VERSION 5.7 ;
  NOWIREEXTENSIONATPIN ON ;
  DIVIDERCHAR "/" ;
  BUSBITCHARS "[]" ;
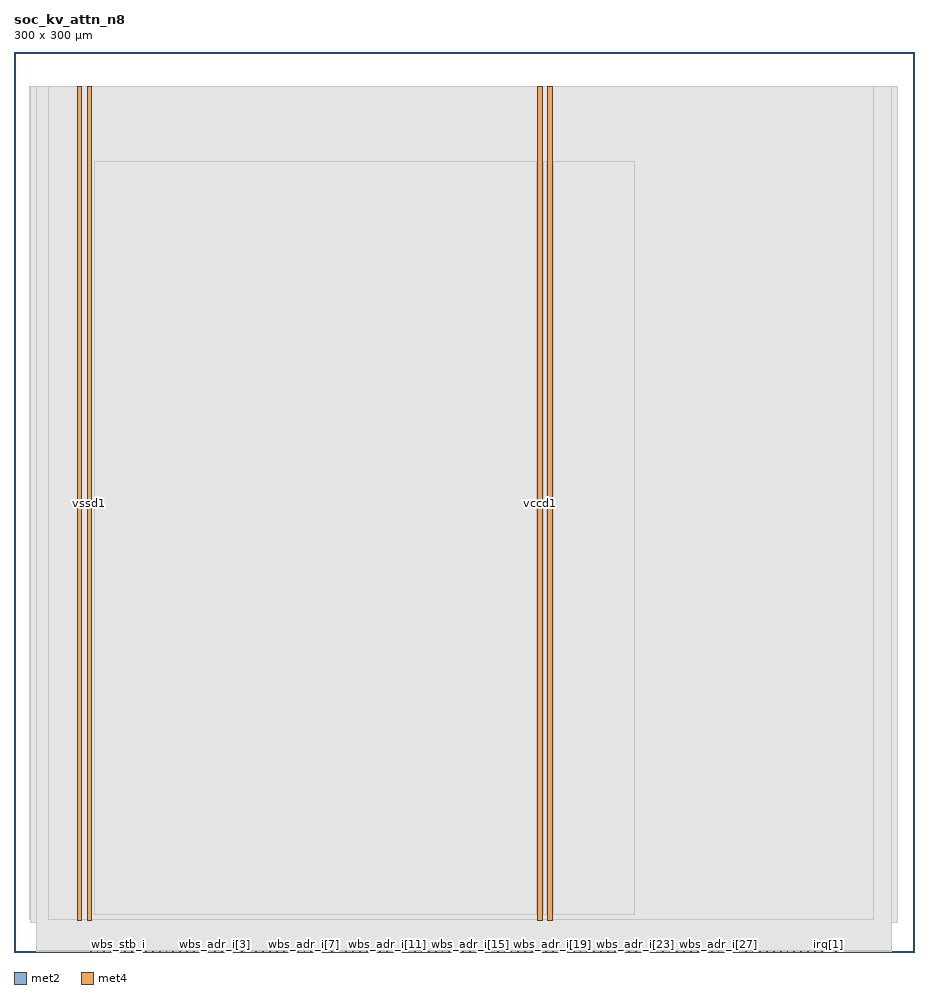
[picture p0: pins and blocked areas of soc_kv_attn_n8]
MACRO soc_kv_attn_n8
  CLASS BLOCK ;
  FOREIGN soc_kv_attn_n8 ;
  ORIGIN 0.000 0.000 ;
  SIZE 300.000 BY 300.000 ;
  PIN irq[0]
    DIRECTION OUTPUT ;
    USE SIGNAL ;
    ANTENNADIFFAREA 2.673000 ;
    PORT
      LAYER met2 ;
        RECT 269.190 0.000 269.470 0.280 ;
    END
  END irq[0]
  PIN irq[1]
    DIRECTION OUTPUT ;
    USE SIGNAL ;
    PORT
      LAYER met2 ;
        RECT 271.490 0.000 271.770 0.280 ;
    END
  END irq[1]
  PIN irq[2]
    DIRECTION OUTPUT ;
    USE SIGNAL ;
    PORT
      LAYER met2 ;
        RECT 273.790 0.000 274.070 0.280 ;
    END
  END irq[2]
  PIN vccd1
    DIRECTION INOUT ;
    USE POWER ;
    PORT
      LAYER met4 ;
        RECT 21.040 10.640 22.640 288.560 ;
    END
    PORT
      LAYER met4 ;
        RECT 174.640 10.640 176.240 288.560 ;
    END
  END vccd1
  PIN vssd1
    DIRECTION INOUT ;
    USE GROUND ;
    PORT
      LAYER met4 ;
        RECT 24.340 10.640 25.940 288.560 ;
    END
    PORT
      LAYER met4 ;
        RECT 177.940 10.640 179.540 288.560 ;
    END
  END vssd1
  PIN wb_clk_i
    DIRECTION INPUT ;
    USE SIGNAL ;
    ANTENNAGATEAREA 1.286700 ;
    ANTENNADIFFAREA 0.434700 ;
    PORT
      LAYER met2 ;
        RECT 25.390 0.000 25.670 0.280 ;
    END
  END wb_clk_i
  PIN wb_rst_i
    DIRECTION INPUT ;
    USE SIGNAL ;
    ANTENNAGATEAREA 0.647700 ;
    ANTENNADIFFAREA 0.434700 ;
    PORT
      LAYER met2 ;
        RECT 27.690 0.000 27.970 0.280 ;
    END
  END wb_rst_i
  PIN wbs_ack_o
    DIRECTION OUTPUT ;
    USE SIGNAL ;
    ANTENNADIFFAREA 2.673000 ;
    PORT
      LAYER met2 ;
        RECT 29.990 0.000 30.270 0.280 ;
    END
  END wbs_ack_o
  PIN wbs_adr_i[0]
    DIRECTION INPUT ;
    USE SIGNAL ;
    PORT
      LAYER met2 ;
        RECT 39.190 0.000 39.470 0.280 ;
    END
  END wbs_adr_i[0]
  PIN wbs_adr_i[10]
    DIRECTION INPUT ;
    USE SIGNAL ;
    ANTENNAGATEAREA 0.560700 ;
    ANTENNADIFFAREA 0.434700 ;
    PORT
      LAYER met2 ;
        RECT 117.390 0.000 117.670 0.280 ;
    END
  END wbs_adr_i[10]
  PIN wbs_adr_i[11]
    DIRECTION INPUT ;
    USE SIGNAL ;
    ANTENNAGATEAREA 0.647700 ;
    ANTENNADIFFAREA 0.434700 ;
    PORT
      LAYER met2 ;
        RECT 124.290 0.000 124.570 0.280 ;
    END
  END wbs_adr_i[11]
  PIN wbs_adr_i[12]
    DIRECTION INPUT ;
    USE SIGNAL ;
    ANTENNAGATEAREA 0.647700 ;
    ANTENNADIFFAREA 0.434700 ;
    PORT
      LAYER met2 ;
        RECT 131.190 0.000 131.470 0.280 ;
    END
  END wbs_adr_i[12]
  PIN wbs_adr_i[13]
    DIRECTION INPUT ;
    USE SIGNAL ;
    ANTENNAGATEAREA 0.647700 ;
    ANTENNADIFFAREA 0.434700 ;
    PORT
      LAYER met2 ;
        RECT 138.090 0.000 138.370 0.280 ;
    END
  END wbs_adr_i[13]
  PIN wbs_adr_i[14]
    DIRECTION INPUT ;
    USE SIGNAL ;
    ANTENNAGATEAREA 0.647700 ;
    ANTENNADIFFAREA 0.434700 ;
    PORT
      LAYER met2 ;
        RECT 144.990 0.000 145.270 0.280 ;
    END
  END wbs_adr_i[14]
  PIN wbs_adr_i[15]
    DIRECTION INPUT ;
    USE SIGNAL ;
    ANTENNAGATEAREA 0.647700 ;
    ANTENNADIFFAREA 0.434700 ;
    PORT
      LAYER met2 ;
        RECT 151.890 0.000 152.170 0.280 ;
    END
  END wbs_adr_i[15]
  PIN wbs_adr_i[16]
    DIRECTION INPUT ;
    USE SIGNAL ;
    ANTENNAGATEAREA 0.647700 ;
    ANTENNADIFFAREA 0.434700 ;
    PORT
      LAYER met2 ;
        RECT 158.790 0.000 159.070 0.280 ;
    END
  END wbs_adr_i[16]
  PIN wbs_adr_i[17]
    DIRECTION INPUT ;
    USE SIGNAL ;
    ANTENNAGATEAREA 0.647700 ;
    ANTENNADIFFAREA 0.434700 ;
    PORT
      LAYER met2 ;
        RECT 165.690 0.000 165.970 0.280 ;
    END
  END wbs_adr_i[17]
  PIN wbs_adr_i[18]
    DIRECTION INPUT ;
    USE SIGNAL ;
    ANTENNAGATEAREA 0.647700 ;
    ANTENNADIFFAREA 0.434700 ;
    PORT
      LAYER met2 ;
        RECT 172.590 0.000 172.870 0.280 ;
    END
  END wbs_adr_i[18]
  PIN wbs_adr_i[19]
    DIRECTION INPUT ;
    USE SIGNAL ;
    ANTENNAGATEAREA 0.647700 ;
    ANTENNADIFFAREA 0.434700 ;
    PORT
      LAYER met2 ;
        RECT 179.490 0.000 179.770 0.280 ;
    END
  END wbs_adr_i[19]
  PIN wbs_adr_i[1]
    DIRECTION INPUT ;
    USE SIGNAL ;
    PORT
      LAYER met2 ;
        RECT 48.390 0.000 48.670 0.280 ;
    END
  END wbs_adr_i[1]
  PIN wbs_adr_i[20]
    DIRECTION INPUT ;
    USE SIGNAL ;
    ANTENNAGATEAREA 0.647700 ;
    ANTENNADIFFAREA 0.434700 ;
    PORT
      LAYER met2 ;
        RECT 186.390 0.000 186.670 0.280 ;
    END
  END wbs_adr_i[20]
  PIN wbs_adr_i[21]
    DIRECTION INPUT ;
    USE SIGNAL ;
    ANTENNAGATEAREA 0.647700 ;
    ANTENNADIFFAREA 0.434700 ;
    PORT
      LAYER met2 ;
        RECT 193.290 0.000 193.570 0.280 ;
    END
  END wbs_adr_i[21]
  PIN wbs_adr_i[22]
    DIRECTION INPUT ;
    USE SIGNAL ;
    ANTENNAGATEAREA 0.560700 ;
    ANTENNADIFFAREA 0.434700 ;
    PORT
      LAYER met2 ;
        RECT 200.190 0.000 200.470 0.280 ;
    END
  END wbs_adr_i[22]
  PIN wbs_adr_i[23]
    DIRECTION INPUT ;
    USE SIGNAL ;
    ANTENNAGATEAREA 0.647700 ;
    ANTENNADIFFAREA 0.434700 ;
    PORT
      LAYER met2 ;
        RECT 207.090 0.000 207.370 0.280 ;
    END
  END wbs_adr_i[23]
  PIN wbs_adr_i[24]
    DIRECTION INPUT ;
    USE SIGNAL ;
    ANTENNAGATEAREA 0.647700 ;
    ANTENNADIFFAREA 0.434700 ;
    PORT
      LAYER met2 ;
        RECT 213.990 0.000 214.270 0.280 ;
    END
  END wbs_adr_i[24]
  PIN wbs_adr_i[25]
    DIRECTION INPUT ;
    USE SIGNAL ;
    ANTENNAGATEAREA 0.647700 ;
    ANTENNADIFFAREA 0.434700 ;
    PORT
      LAYER met2 ;
        RECT 220.890 0.000 221.170 0.280 ;
    END
  END wbs_adr_i[25]
  PIN wbs_adr_i[26]
    DIRECTION INPUT ;
    USE SIGNAL ;
    ANTENNAGATEAREA 0.560700 ;
    ANTENNADIFFAREA 0.434700 ;
    PORT
      LAYER met2 ;
        RECT 227.790 0.000 228.070 0.280 ;
    END
  END wbs_adr_i[26]
  PIN wbs_adr_i[27]
    DIRECTION INPUT ;
    USE SIGNAL ;
    ANTENNAGATEAREA 0.647700 ;
    ANTENNADIFFAREA 0.434700 ;
    PORT
      LAYER met2 ;
        RECT 234.690 0.000 234.970 0.280 ;
    END
  END wbs_adr_i[27]
  PIN wbs_adr_i[28]
    DIRECTION INPUT ;
    USE SIGNAL ;
    ANTENNAGATEAREA 0.647700 ;
    ANTENNADIFFAREA 0.434700 ;
    PORT
      LAYER met2 ;
        RECT 241.590 0.000 241.870 0.280 ;
    END
  END wbs_adr_i[28]
  PIN wbs_adr_i[29]
    DIRECTION INPUT ;
    USE SIGNAL ;
    ANTENNAGATEAREA 0.647700 ;
    ANTENNADIFFAREA 0.434700 ;
    PORT
      LAYER met2 ;
        RECT 248.490 0.000 248.770 0.280 ;
    END
  END wbs_adr_i[29]
  PIN wbs_adr_i[2]
    DIRECTION INPUT ;
    USE SIGNAL ;
    ANTENNAGATEAREA 0.560700 ;
    ANTENNADIFFAREA 0.434700 ;
    PORT
      LAYER met2 ;
        RECT 57.590 0.000 57.870 0.280 ;
    END
  END wbs_adr_i[2]
  PIN wbs_adr_i[30]
    DIRECTION INPUT ;
    USE SIGNAL ;
    ANTENNAGATEAREA 0.647700 ;
    ANTENNADIFFAREA 0.434700 ;
    PORT
      LAYER met2 ;
        RECT 255.390 0.000 255.670 0.280 ;
    END
  END wbs_adr_i[30]
  PIN wbs_adr_i[31]
    DIRECTION INPUT ;
    USE SIGNAL ;
    ANTENNAGATEAREA 0.647700 ;
    ANTENNADIFFAREA 0.434700 ;
    PORT
      LAYER met2 ;
        RECT 262.290 0.000 262.570 0.280 ;
    END
  END wbs_adr_i[31]
  PIN wbs_adr_i[3]
    DIRECTION INPUT ;
    USE SIGNAL ;
    ANTENNAGATEAREA 0.560700 ;
    ANTENNADIFFAREA 0.434700 ;
    PORT
      LAYER met2 ;
        RECT 66.790 0.000 67.070 0.280 ;
    END
  END wbs_adr_i[3]
  PIN wbs_adr_i[4]
    DIRECTION INPUT ;
    USE SIGNAL ;
    ANTENNAGATEAREA 0.560700 ;
    ANTENNADIFFAREA 0.434700 ;
    PORT
      LAYER met2 ;
        RECT 75.990 0.000 76.270 0.280 ;
    END
  END wbs_adr_i[4]
  PIN wbs_adr_i[5]
    DIRECTION INPUT ;
    USE SIGNAL ;
    ANTENNAGATEAREA 0.560700 ;
    ANTENNADIFFAREA 0.434700 ;
    PORT
      LAYER met2 ;
        RECT 82.890 0.000 83.170 0.280 ;
    END
  END wbs_adr_i[5]
  PIN wbs_adr_i[6]
    DIRECTION INPUT ;
    USE SIGNAL ;
    ANTENNAGATEAREA 0.560700 ;
    ANTENNADIFFAREA 0.434700 ;
    PORT
      LAYER met2 ;
        RECT 89.790 0.000 90.070 0.280 ;
    END
  END wbs_adr_i[6]
  PIN wbs_adr_i[7]
    DIRECTION INPUT ;
    USE SIGNAL ;
    ANTENNAGATEAREA 0.560700 ;
    ANTENNADIFFAREA 0.434700 ;
    PORT
      LAYER met2 ;
        RECT 96.690 0.000 96.970 0.280 ;
    END
  END wbs_adr_i[7]
  PIN wbs_adr_i[8]
    DIRECTION INPUT ;
    USE SIGNAL ;
    ANTENNAGATEAREA 0.647700 ;
    ANTENNADIFFAREA 0.434700 ;
    PORT
      LAYER met2 ;
        RECT 103.590 0.000 103.870 0.280 ;
    END
  END wbs_adr_i[8]
  PIN wbs_adr_i[9]
    DIRECTION INPUT ;
    USE SIGNAL ;
    ANTENNAGATEAREA 0.647700 ;
    ANTENNADIFFAREA 0.434700 ;
    PORT
      LAYER met2 ;
        RECT 110.490 0.000 110.770 0.280 ;
    END
  END wbs_adr_i[9]
  PIN wbs_cyc_i
    DIRECTION INPUT ;
    USE SIGNAL ;
    ANTENNAGATEAREA 0.647700 ;
    ANTENNADIFFAREA 0.434700 ;
    PORT
      LAYER met2 ;
        RECT 32.290 0.000 32.570 0.280 ;
    END
  END wbs_cyc_i
  PIN wbs_dat_i[0]
    DIRECTION INPUT ;
    USE SIGNAL ;
    ANTENNAGATEAREA 0.560700 ;
    ANTENNADIFFAREA 0.434700 ;
    PORT
      LAYER met2 ;
        RECT 41.490 0.000 41.770 0.280 ;
    END
  END wbs_dat_i[0]
  PIN wbs_dat_i[10]
    DIRECTION INPUT ;
    USE SIGNAL ;
    PORT
      LAYER met2 ;
        RECT 119.690 0.000 119.970 0.280 ;
    END
  END wbs_dat_i[10]
  PIN wbs_dat_i[11]
    DIRECTION INPUT ;
    USE SIGNAL ;
    PORT
      LAYER met2 ;
        RECT 126.590 0.000 126.870 0.280 ;
    END
  END wbs_dat_i[11]
  PIN wbs_dat_i[12]
    DIRECTION INPUT ;
    USE SIGNAL ;
    PORT
      LAYER met2 ;
        RECT 133.490 0.000 133.770 0.280 ;
    END
  END wbs_dat_i[12]
  PIN wbs_dat_i[13]
    DIRECTION INPUT ;
    USE SIGNAL ;
    PORT
      LAYER met2 ;
        RECT 140.390 0.000 140.670 0.280 ;
    END
  END wbs_dat_i[13]
  PIN wbs_dat_i[14]
    DIRECTION INPUT ;
    USE SIGNAL ;
    PORT
      LAYER met2 ;
        RECT 147.290 0.000 147.570 0.280 ;
    END
  END wbs_dat_i[14]
  PIN wbs_dat_i[15]
    DIRECTION INPUT ;
    USE SIGNAL ;
    PORT
      LAYER met2 ;
        RECT 154.190 0.000 154.470 0.280 ;
    END
  END wbs_dat_i[15]
  PIN wbs_dat_i[16]
    DIRECTION INPUT ;
    USE SIGNAL ;
    PORT
      LAYER met2 ;
        RECT 161.090 0.000 161.370 0.280 ;
    END
  END wbs_dat_i[16]
  PIN wbs_dat_i[17]
    DIRECTION INPUT ;
    USE SIGNAL ;
    PORT
      LAYER met2 ;
        RECT 167.990 0.000 168.270 0.280 ;
    END
  END wbs_dat_i[17]
  PIN wbs_dat_i[18]
    DIRECTION INPUT ;
    USE SIGNAL ;
    PORT
      LAYER met2 ;
        RECT 174.890 0.000 175.170 0.280 ;
    END
  END wbs_dat_i[18]
  PIN wbs_dat_i[19]
    DIRECTION INPUT ;
    USE SIGNAL ;
    PORT
      LAYER met2 ;
        RECT 181.790 0.000 182.070 0.280 ;
    END
  END wbs_dat_i[19]
  PIN wbs_dat_i[1]
    DIRECTION INPUT ;
    USE SIGNAL ;
    ANTENNAGATEAREA 0.560700 ;
    ANTENNADIFFAREA 0.434700 ;
    PORT
      LAYER met2 ;
        RECT 50.690 0.000 50.970 0.280 ;
    END
  END wbs_dat_i[1]
  PIN wbs_dat_i[20]
    DIRECTION INPUT ;
    USE SIGNAL ;
    PORT
      LAYER met2 ;
        RECT 188.690 0.000 188.970 0.280 ;
    END
  END wbs_dat_i[20]
  PIN wbs_dat_i[21]
    DIRECTION INPUT ;
    USE SIGNAL ;
    PORT
      LAYER met2 ;
        RECT 195.590 0.000 195.870 0.280 ;
    END
  END wbs_dat_i[21]
  PIN wbs_dat_i[22]
    DIRECTION INPUT ;
    USE SIGNAL ;
    PORT
      LAYER met2 ;
        RECT 202.490 0.000 202.770 0.280 ;
    END
  END wbs_dat_i[22]
  PIN wbs_dat_i[23]
    DIRECTION INPUT ;
    USE SIGNAL ;
    PORT
      LAYER met2 ;
        RECT 209.390 0.000 209.670 0.280 ;
    END
  END wbs_dat_i[23]
  PIN wbs_dat_i[24]
    DIRECTION INPUT ;
    USE SIGNAL ;
    PORT
      LAYER met2 ;
        RECT 216.290 0.000 216.570 0.280 ;
    END
  END wbs_dat_i[24]
  PIN wbs_dat_i[25]
    DIRECTION INPUT ;
    USE SIGNAL ;
    PORT
      LAYER met2 ;
        RECT 223.190 0.000 223.470 0.280 ;
    END
  END wbs_dat_i[25]
  PIN wbs_dat_i[26]
    DIRECTION INPUT ;
    USE SIGNAL ;
    PORT
      LAYER met2 ;
        RECT 230.090 0.000 230.370 0.280 ;
    END
  END wbs_dat_i[26]
  PIN wbs_dat_i[27]
    DIRECTION INPUT ;
    USE SIGNAL ;
    PORT
      LAYER met2 ;
        RECT 236.990 0.000 237.270 0.280 ;
    END
  END wbs_dat_i[27]
  PIN wbs_dat_i[28]
    DIRECTION INPUT ;
    USE SIGNAL ;
    PORT
      LAYER met2 ;
        RECT 243.890 0.000 244.170 0.280 ;
    END
  END wbs_dat_i[28]
  PIN wbs_dat_i[29]
    DIRECTION INPUT ;
    USE SIGNAL ;
    PORT
      LAYER met2 ;
        RECT 250.790 0.000 251.070 0.280 ;
    END
  END wbs_dat_i[29]
  PIN wbs_dat_i[2]
    DIRECTION INPUT ;
    USE SIGNAL ;
    ANTENNAGATEAREA 0.560700 ;
    ANTENNADIFFAREA 0.434700 ;
    PORT
      LAYER met2 ;
        RECT 59.890 0.000 60.170 0.280 ;
    END
  END wbs_dat_i[2]
  PIN wbs_dat_i[30]
    DIRECTION INPUT ;
    USE SIGNAL ;
    PORT
      LAYER met2 ;
        RECT 257.690 0.000 257.970 0.280 ;
    END
  END wbs_dat_i[30]
  PIN wbs_dat_i[31]
    DIRECTION INPUT ;
    USE SIGNAL ;
    PORT
      LAYER met2 ;
        RECT 264.590 0.000 264.870 0.280 ;
    END
  END wbs_dat_i[31]
  PIN wbs_dat_i[3]
    DIRECTION INPUT ;
    USE SIGNAL ;
    ANTENNAGATEAREA 0.560700 ;
    ANTENNADIFFAREA 0.434700 ;
    PORT
      LAYER met2 ;
        RECT 69.090 0.000 69.370 0.280 ;
    END
  END wbs_dat_i[3]
  PIN wbs_dat_i[4]
    DIRECTION INPUT ;
    USE SIGNAL ;
    ANTENNAGATEAREA 0.560700 ;
    ANTENNADIFFAREA 0.434700 ;
    PORT
      LAYER met2 ;
        RECT 78.290 0.000 78.570 0.280 ;
    END
  END wbs_dat_i[4]
  PIN wbs_dat_i[5]
    DIRECTION INPUT ;
    USE SIGNAL ;
    ANTENNAGATEAREA 0.560700 ;
    ANTENNADIFFAREA 0.434700 ;
    PORT
      LAYER met2 ;
        RECT 85.190 0.000 85.470 0.280 ;
    END
  END wbs_dat_i[5]
  PIN wbs_dat_i[6]
    DIRECTION INPUT ;
    USE SIGNAL ;
    ANTENNAGATEAREA 0.560700 ;
    ANTENNADIFFAREA 0.434700 ;
    PORT
      LAYER met2 ;
        RECT 92.090 0.000 92.370 0.280 ;
    END
  END wbs_dat_i[6]
  PIN wbs_dat_i[7]
    DIRECTION INPUT ;
    USE SIGNAL ;
    ANTENNAGATEAREA 0.560700 ;
    ANTENNADIFFAREA 0.434700 ;
    PORT
      LAYER met2 ;
        RECT 98.990 0.000 99.270 0.280 ;
    END
  END wbs_dat_i[7]
  PIN wbs_dat_i[8]
    DIRECTION INPUT ;
    USE SIGNAL ;
    ANTENNAGATEAREA 0.560700 ;
    ANTENNADIFFAREA 0.434700 ;
    PORT
      LAYER met2 ;
        RECT 105.890 0.000 106.170 0.280 ;
    END
  END wbs_dat_i[8]
  PIN wbs_dat_i[9]
    DIRECTION INPUT ;
    USE SIGNAL ;
    PORT
      LAYER met2 ;
        RECT 112.790 0.000 113.070 0.280 ;
    END
  END wbs_dat_i[9]
  PIN wbs_dat_o[0]
    DIRECTION OUTPUT ;
    USE SIGNAL ;
    ANTENNADIFFAREA 2.673000 ;
    PORT
      LAYER met2 ;
        RECT 43.790 0.000 44.070 0.280 ;
    END
  END wbs_dat_o[0]
  PIN wbs_dat_o[10]
    DIRECTION OUTPUT ;
    USE SIGNAL ;
    ANTENNADIFFAREA 2.673000 ;
    PORT
      LAYER met2 ;
        RECT 121.990 0.000 122.270 0.280 ;
    END
  END wbs_dat_o[10]
  PIN wbs_dat_o[11]
    DIRECTION OUTPUT ;
    USE SIGNAL ;
    ANTENNADIFFAREA 2.673000 ;
    PORT
      LAYER met2 ;
        RECT 128.890 0.000 129.170 0.280 ;
    END
  END wbs_dat_o[11]
  PIN wbs_dat_o[12]
    DIRECTION OUTPUT ;
    USE SIGNAL ;
    ANTENNADIFFAREA 2.673000 ;
    PORT
      LAYER met2 ;
        RECT 135.790 0.000 136.070 0.280 ;
    END
  END wbs_dat_o[12]
  PIN wbs_dat_o[13]
    DIRECTION OUTPUT ;
    USE SIGNAL ;
    ANTENNADIFFAREA 2.673000 ;
    PORT
      LAYER met2 ;
        RECT 142.690 0.000 142.970 0.280 ;
    END
  END wbs_dat_o[13]
  PIN wbs_dat_o[14]
    DIRECTION OUTPUT ;
    USE SIGNAL ;
    ANTENNADIFFAREA 2.673000 ;
    PORT
      LAYER met2 ;
        RECT 149.590 0.000 149.870 0.280 ;
    END
  END wbs_dat_o[14]
  PIN wbs_dat_o[15]
    DIRECTION OUTPUT ;
    USE SIGNAL ;
    ANTENNADIFFAREA 2.673000 ;
    PORT
      LAYER met2 ;
        RECT 156.490 0.000 156.770 0.280 ;
    END
  END wbs_dat_o[15]
  PIN wbs_dat_o[16]
    DIRECTION OUTPUT ;
    USE SIGNAL ;
    ANTENNADIFFAREA 2.673000 ;
    PORT
      LAYER met2 ;
        RECT 163.390 0.000 163.670 0.280 ;
    END
  END wbs_dat_o[16]
  PIN wbs_dat_o[17]
    DIRECTION OUTPUT ;
    USE SIGNAL ;
    ANTENNADIFFAREA 2.673000 ;
    PORT
      LAYER met2 ;
        RECT 170.290 0.000 170.570 0.280 ;
    END
  END wbs_dat_o[17]
  PIN wbs_dat_o[18]
    DIRECTION OUTPUT ;
    USE SIGNAL ;
    ANTENNADIFFAREA 2.673000 ;
    PORT
      LAYER met2 ;
        RECT 177.190 0.000 177.470 0.280 ;
    END
  END wbs_dat_o[18]
  PIN wbs_dat_o[19]
    DIRECTION OUTPUT ;
    USE SIGNAL ;
    ANTENNADIFFAREA 2.673000 ;
    PORT
      LAYER met2 ;
        RECT 184.090 0.000 184.370 0.280 ;
    END
  END wbs_dat_o[19]
  PIN wbs_dat_o[1]
    DIRECTION OUTPUT ;
    USE SIGNAL ;
    ANTENNADIFFAREA 2.673000 ;
    PORT
      LAYER met2 ;
        RECT 52.990 0.000 53.270 0.280 ;
    END
  END wbs_dat_o[1]
  PIN wbs_dat_o[20]
    DIRECTION OUTPUT ;
    USE SIGNAL ;
    ANTENNADIFFAREA 2.673000 ;
    PORT
      LAYER met2 ;
        RECT 190.990 0.000 191.270 0.280 ;
    END
  END wbs_dat_o[20]
  PIN wbs_dat_o[21]
    DIRECTION OUTPUT ;
    USE SIGNAL ;
    PORT
      LAYER met2 ;
        RECT 197.890 0.000 198.170 0.280 ;
    END
  END wbs_dat_o[21]
  PIN wbs_dat_o[22]
    DIRECTION OUTPUT ;
    USE SIGNAL ;
    ANTENNADIFFAREA 2.673000 ;
    PORT
      LAYER met2 ;
        RECT 204.790 0.000 205.070 0.280 ;
    END
  END wbs_dat_o[22]
  PIN wbs_dat_o[23]
    DIRECTION OUTPUT ;
    USE SIGNAL ;
    PORT
      LAYER met2 ;
        RECT 211.690 0.000 211.970 0.280 ;
    END
  END wbs_dat_o[23]
  PIN wbs_dat_o[24]
    DIRECTION OUTPUT ;
    USE SIGNAL ;
    ANTENNADIFFAREA 2.673000 ;
    PORT
      LAYER met2 ;
        RECT 218.590 0.000 218.870 0.280 ;
    END
  END wbs_dat_o[24]
  PIN wbs_dat_o[25]
    DIRECTION OUTPUT ;
    USE SIGNAL ;
    ANTENNADIFFAREA 2.673000 ;
    PORT
      LAYER met2 ;
        RECT 225.490 0.000 225.770 0.280 ;
    END
  END wbs_dat_o[25]
  PIN wbs_dat_o[26]
    DIRECTION OUTPUT ;
    USE SIGNAL ;
    PORT
      LAYER met2 ;
        RECT 232.390 0.000 232.670 0.280 ;
    END
  END wbs_dat_o[26]
  PIN wbs_dat_o[27]
    DIRECTION OUTPUT ;
    USE SIGNAL ;
    PORT
      LAYER met2 ;
        RECT 239.290 0.000 239.570 0.280 ;
    END
  END wbs_dat_o[27]
  PIN wbs_dat_o[28]
    DIRECTION OUTPUT ;
    USE SIGNAL ;
    ANTENNADIFFAREA 2.673000 ;
    PORT
      LAYER met2 ;
        RECT 246.190 0.000 246.470 0.280 ;
    END
  END wbs_dat_o[28]
  PIN wbs_dat_o[29]
    DIRECTION OUTPUT ;
    USE SIGNAL ;
    PORT
      LAYER met2 ;
        RECT 253.090 0.000 253.370 0.280 ;
    END
  END wbs_dat_o[29]
  PIN wbs_dat_o[2]
    DIRECTION OUTPUT ;
    USE SIGNAL ;
    ANTENNADIFFAREA 2.673000 ;
    PORT
      LAYER met2 ;
        RECT 62.190 0.000 62.470 0.280 ;
    END
  END wbs_dat_o[2]
  PIN wbs_dat_o[30]
    DIRECTION OUTPUT ;
    USE SIGNAL ;
    ANTENNADIFFAREA 2.673000 ;
    PORT
      LAYER met2 ;
        RECT 259.990 0.000 260.270 0.280 ;
    END
  END wbs_dat_o[30]
  PIN wbs_dat_o[31]
    DIRECTION OUTPUT ;
    USE SIGNAL ;
    PORT
      LAYER met2 ;
        RECT 266.890 0.000 267.170 0.280 ;
    END
  END wbs_dat_o[31]
  PIN wbs_dat_o[3]
    DIRECTION OUTPUT ;
    USE SIGNAL ;
    ANTENNADIFFAREA 2.673000 ;
    PORT
      LAYER met2 ;
        RECT 71.390 0.000 71.670 0.280 ;
    END
  END wbs_dat_o[3]
  PIN wbs_dat_o[4]
    DIRECTION OUTPUT ;
    USE SIGNAL ;
    ANTENNADIFFAREA 2.673000 ;
    PORT
      LAYER met2 ;
        RECT 80.590 0.000 80.870 0.280 ;
    END
  END wbs_dat_o[4]
  PIN wbs_dat_o[5]
    DIRECTION OUTPUT ;
    USE SIGNAL ;
    ANTENNADIFFAREA 2.673000 ;
    PORT
      LAYER met2 ;
        RECT 87.490 0.000 87.770 0.280 ;
    END
  END wbs_dat_o[5]
  PIN wbs_dat_o[6]
    DIRECTION OUTPUT ;
    USE SIGNAL ;
    ANTENNADIFFAREA 2.673000 ;
    PORT
      LAYER met2 ;
        RECT 94.390 0.000 94.670 0.280 ;
    END
  END wbs_dat_o[6]
  PIN wbs_dat_o[7]
    DIRECTION OUTPUT ;
    USE SIGNAL ;
    ANTENNADIFFAREA 2.673000 ;
    PORT
      LAYER met2 ;
        RECT 101.290 0.000 101.570 0.280 ;
    END
  END wbs_dat_o[7]
  PIN wbs_dat_o[8]
    DIRECTION OUTPUT ;
    USE SIGNAL ;
    ANTENNADIFFAREA 2.673000 ;
    PORT
      LAYER met2 ;
        RECT 108.190 0.000 108.470 0.280 ;
    END
  END wbs_dat_o[8]
  PIN wbs_dat_o[9]
    DIRECTION OUTPUT ;
    USE SIGNAL ;
    ANTENNADIFFAREA 2.673000 ;
    PORT
      LAYER met2 ;
        RECT 115.090 0.000 115.370 0.280 ;
    END
  END wbs_dat_o[9]
  PIN wbs_sel_i[0]
    DIRECTION INPUT ;
    USE SIGNAL ;
    ANTENNAGATEAREA 0.560700 ;
    ANTENNADIFFAREA 0.434700 ;
    PORT
      LAYER met2 ;
        RECT 46.090 0.000 46.370 0.280 ;
    END
  END wbs_sel_i[0]
  PIN wbs_sel_i[1]
    DIRECTION INPUT ;
    USE SIGNAL ;
    ANTENNAGATEAREA 0.647700 ;
    ANTENNADIFFAREA 0.434700 ;
    PORT
      LAYER met2 ;
        RECT 55.290 0.000 55.570 0.280 ;
    END
  END wbs_sel_i[1]
  PIN wbs_sel_i[2]
    DIRECTION INPUT ;
    USE SIGNAL ;
    ANTENNAGATEAREA 0.560700 ;
    ANTENNADIFFAREA 0.434700 ;
    PORT
      LAYER met2 ;
        RECT 64.490 0.000 64.770 0.280 ;
    END
  END wbs_sel_i[2]
  PIN wbs_sel_i[3]
    DIRECTION INPUT ;
    USE SIGNAL ;
    ANTENNAGATEAREA 0.560700 ;
    ANTENNADIFFAREA 0.434700 ;
    PORT
      LAYER met2 ;
        RECT 73.690 0.000 73.970 0.280 ;
    END
  END wbs_sel_i[3]
  PIN wbs_stb_i
    DIRECTION INPUT ;
    USE SIGNAL ;
    ANTENNAGATEAREA 0.647700 ;
    ANTENNADIFFAREA 0.434700 ;
    PORT
      LAYER met2 ;
        RECT 34.590 0.000 34.870 0.280 ;
    END
  END wbs_stb_i
  PIN wbs_we_i
    DIRECTION INPUT ;
    USE SIGNAL ;
    ANTENNAGATEAREA 0.647700 ;
    ANTENNADIFFAREA 0.434700 ;
    PORT
      LAYER met2 ;
        RECT 36.890 0.000 37.170 0.280 ;
    END
  END wbs_we_i
  OBS
      LAYER nwell ;
        RECT 5.330 10.795 294.590 288.405 ;
      LAYER li1 ;
        RECT 5.520 10.795 294.400 288.405 ;
      LAYER met1 ;
        RECT 5.520 9.900 294.400 288.560 ;
      LAYER met2 ;
        RECT 7.460 0.560 292.460 288.505 ;
        RECT 7.460 0.070 25.110 0.560 ;
        RECT 25.950 0.070 27.410 0.560 ;
        RECT 28.250 0.070 29.710 0.560 ;
        RECT 30.550 0.070 32.010 0.560 ;
        RECT 32.850 0.070 34.310 0.560 ;
        RECT 35.150 0.070 36.610 0.560 ;
        RECT 37.450 0.070 38.910 0.560 ;
        RECT 39.750 0.070 41.210 0.560 ;
        RECT 42.050 0.070 43.510 0.560 ;
        RECT 44.350 0.070 45.810 0.560 ;
        RECT 46.650 0.070 48.110 0.560 ;
        RECT 48.950 0.070 50.410 0.560 ;
        RECT 51.250 0.070 52.710 0.560 ;
        RECT 53.550 0.070 55.010 0.560 ;
        RECT 55.850 0.070 57.310 0.560 ;
        RECT 58.150 0.070 59.610 0.560 ;
        RECT 60.450 0.070 61.910 0.560 ;
        RECT 62.750 0.070 64.210 0.560 ;
        RECT 65.050 0.070 66.510 0.560 ;
        RECT 67.350 0.070 68.810 0.560 ;
        RECT 69.650 0.070 71.110 0.560 ;
        RECT 71.950 0.070 73.410 0.560 ;
        RECT 74.250 0.070 75.710 0.560 ;
        RECT 76.550 0.070 78.010 0.560 ;
        RECT 78.850 0.070 80.310 0.560 ;
        RECT 81.150 0.070 82.610 0.560 ;
        RECT 83.450 0.070 84.910 0.560 ;
        RECT 85.750 0.070 87.210 0.560 ;
        RECT 88.050 0.070 89.510 0.560 ;
        RECT 90.350 0.070 91.810 0.560 ;
        RECT 92.650 0.070 94.110 0.560 ;
        RECT 94.950 0.070 96.410 0.560 ;
        RECT 97.250 0.070 98.710 0.560 ;
        RECT 99.550 0.070 101.010 0.560 ;
        RECT 101.850 0.070 103.310 0.560 ;
        RECT 104.150 0.070 105.610 0.560 ;
        RECT 106.450 0.070 107.910 0.560 ;
        RECT 108.750 0.070 110.210 0.560 ;
        RECT 111.050 0.070 112.510 0.560 ;
        RECT 113.350 0.070 114.810 0.560 ;
        RECT 115.650 0.070 117.110 0.560 ;
        RECT 117.950 0.070 119.410 0.560 ;
        RECT 120.250 0.070 121.710 0.560 ;
        RECT 122.550 0.070 124.010 0.560 ;
        RECT 124.850 0.070 126.310 0.560 ;
        RECT 127.150 0.070 128.610 0.560 ;
        RECT 129.450 0.070 130.910 0.560 ;
        RECT 131.750 0.070 133.210 0.560 ;
        RECT 134.050 0.070 135.510 0.560 ;
        RECT 136.350 0.070 137.810 0.560 ;
        RECT 138.650 0.070 140.110 0.560 ;
        RECT 140.950 0.070 142.410 0.560 ;
        RECT 143.250 0.070 144.710 0.560 ;
        RECT 145.550 0.070 147.010 0.560 ;
        RECT 147.850 0.070 149.310 0.560 ;
        RECT 150.150 0.070 151.610 0.560 ;
        RECT 152.450 0.070 153.910 0.560 ;
        RECT 154.750 0.070 156.210 0.560 ;
        RECT 157.050 0.070 158.510 0.560 ;
        RECT 159.350 0.070 160.810 0.560 ;
        RECT 161.650 0.070 163.110 0.560 ;
        RECT 163.950 0.070 165.410 0.560 ;
        RECT 166.250 0.070 167.710 0.560 ;
        RECT 168.550 0.070 170.010 0.560 ;
        RECT 170.850 0.070 172.310 0.560 ;
        RECT 173.150 0.070 174.610 0.560 ;
        RECT 175.450 0.070 176.910 0.560 ;
        RECT 177.750 0.070 179.210 0.560 ;
        RECT 180.050 0.070 181.510 0.560 ;
        RECT 182.350 0.070 183.810 0.560 ;
        RECT 184.650 0.070 186.110 0.560 ;
        RECT 186.950 0.070 188.410 0.560 ;
        RECT 189.250 0.070 190.710 0.560 ;
        RECT 191.550 0.070 193.010 0.560 ;
        RECT 193.850 0.070 195.310 0.560 ;
        RECT 196.150 0.070 197.610 0.560 ;
        RECT 198.450 0.070 199.910 0.560 ;
        RECT 200.750 0.070 202.210 0.560 ;
        RECT 203.050 0.070 204.510 0.560 ;
        RECT 205.350 0.070 206.810 0.560 ;
        RECT 207.650 0.070 209.110 0.560 ;
        RECT 209.950 0.070 211.410 0.560 ;
        RECT 212.250 0.070 213.710 0.560 ;
        RECT 214.550 0.070 216.010 0.560 ;
        RECT 216.850 0.070 218.310 0.560 ;
        RECT 219.150 0.070 220.610 0.560 ;
        RECT 221.450 0.070 222.910 0.560 ;
        RECT 223.750 0.070 225.210 0.560 ;
        RECT 226.050 0.070 227.510 0.560 ;
        RECT 228.350 0.070 229.810 0.560 ;
        RECT 230.650 0.070 232.110 0.560 ;
        RECT 232.950 0.070 234.410 0.560 ;
        RECT 235.250 0.070 236.710 0.560 ;
        RECT 237.550 0.070 239.010 0.560 ;
        RECT 239.850 0.070 241.310 0.560 ;
        RECT 242.150 0.070 243.610 0.560 ;
        RECT 244.450 0.070 245.910 0.560 ;
        RECT 246.750 0.070 248.210 0.560 ;
        RECT 249.050 0.070 250.510 0.560 ;
        RECT 251.350 0.070 252.810 0.560 ;
        RECT 253.650 0.070 255.110 0.560 ;
        RECT 255.950 0.070 257.410 0.560 ;
        RECT 258.250 0.070 259.710 0.560 ;
        RECT 260.550 0.070 262.010 0.560 ;
        RECT 262.850 0.070 264.310 0.560 ;
        RECT 265.150 0.070 266.610 0.560 ;
        RECT 267.450 0.070 268.910 0.560 ;
        RECT 269.750 0.070 271.210 0.560 ;
        RECT 272.050 0.070 273.510 0.560 ;
        RECT 274.350 0.070 292.460 0.560 ;
      LAYER met3 ;
        RECT 11.565 10.715 286.515 288.485 ;
      LAYER met4 ;
        RECT 26.975 12.415 174.240 263.665 ;
        RECT 176.640 12.415 177.540 263.665 ;
        RECT 179.940 12.415 206.705 263.665 ;
  END
END soc_kv_attn_n8
END LIBRARY

